###############################################################
#  Generated by:      Cadence Innovus 21.14-s109_1
#  OS:                Linux x86_64(Host ID miet-cad-edu)
#  Generated on:      Sat Nov 14 11:48:11 2026
#  Design:            statistics_unit
#  Command:           write_lef_abstract -stripe_pins -top_layer 5 -no_cut_obs ./out/statistics_unit.lef
###############################################################

VERSION 5.8 ;

BUSBITCHARS "[]" ;
DIVIDERCHAR "/" ;

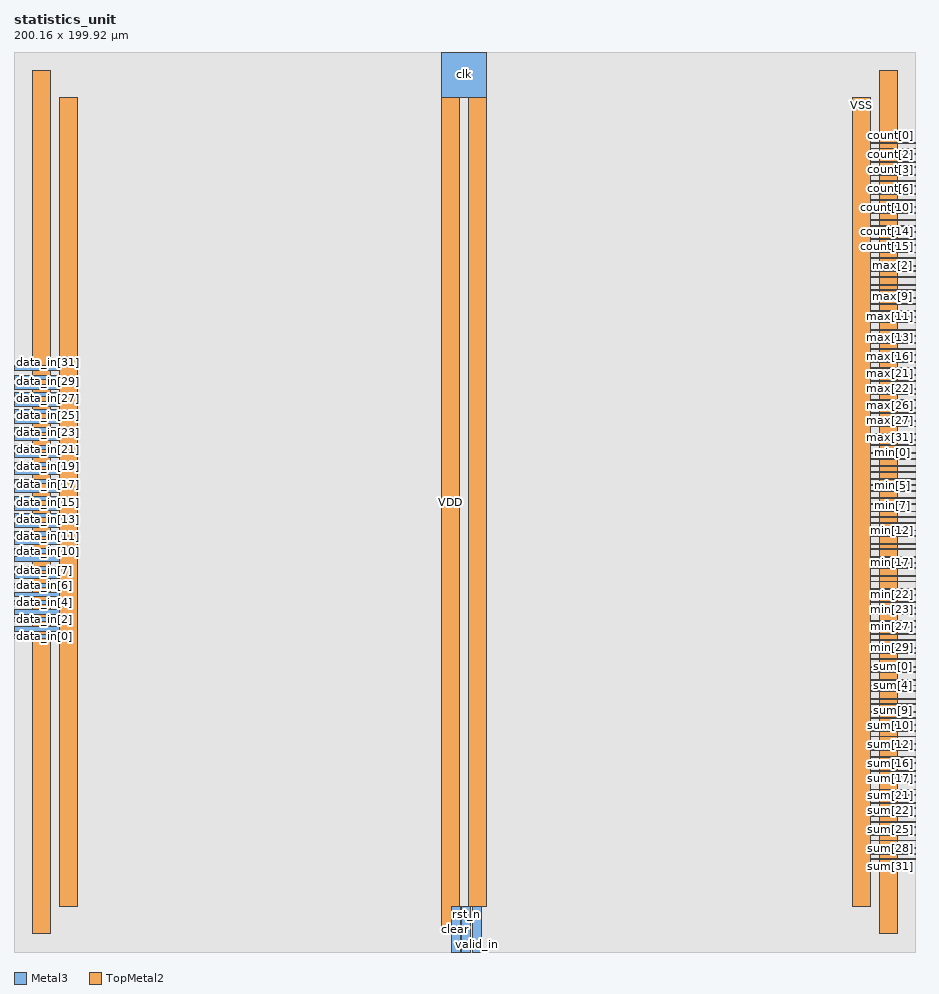
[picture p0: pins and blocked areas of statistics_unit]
MACRO statistics_unit
  CLASS BLOCK ;
  SIZE 200.160000 BY 199.920000 ;
  FOREIGN statistics_unit 0.000000 0.000000 ;
  ORIGIN 0 0 ;
  SYMMETRY X Y R90 ;
  PIN clk
    DIRECTION INPUT ;
    USE SIGNAL ;
    PORT
      LAYER Metal3 ;
        RECT 95.000000 189.920000 105.000000 199.920000 ;
    END
  END clk
  PIN rst_n
    DIRECTION INPUT ;
    USE SIGNAL ;
    PORT
      LAYER Metal3 ;
        RECT 99.480000 0.000000 101.480000 10.000000 ;
    END
  END rst_n
  PIN clear
    DIRECTION INPUT ;
    USE SIGNAL ;
    PORT
      LAYER Metal3 ;
        RECT 97.080000 0.000000 99.080000 10.000000 ;
    END
  END clear
  PIN valid_in
    DIRECTION INPUT ;
    USE SIGNAL ;
    PORT
      LAYER Metal3 ;
        RECT 101.880000 0.000000 103.880000 10.000000 ;
    END
  END valid_in
  PIN data_in[31]
    DIRECTION INPUT ;
    USE SIGNAL ;
    PORT
      LAYER Metal3 ;
        RECT 0.000000 129.260000 10.000000 130.260000 ;
    END
  END data_in[31]
  PIN data_in[30]
    DIRECTION INPUT ;
    USE SIGNAL ;
    PORT
      LAYER Metal3 ;
        RECT 0.000000 127.160000 10.000000 128.160000 ;
    END
  END data_in[30]
  PIN data_in[29]
    DIRECTION INPUT ;
    USE SIGNAL ;
    PORT
      LAYER Metal3 ;
        RECT 0.000000 125.060000 10.000000 126.060000 ;
    END
  END data_in[29]
  PIN data_in[28]
    DIRECTION INPUT ;
    USE SIGNAL ;
    PORT
      LAYER Metal3 ;
        RECT 0.000000 123.380000 10.000000 124.380000 ;
    END
  END data_in[28]
  PIN data_in[27]
    DIRECTION INPUT ;
    USE SIGNAL ;
    PORT
      LAYER Metal3 ;
        RECT 0.000000 121.280000 10.000000 122.280000 ;
    END
  END data_in[27]
  PIN data_in[26]
    DIRECTION INPUT ;
    USE SIGNAL ;
    PORT
      LAYER Metal3 ;
        RECT 0.000000 119.600000 10.000000 120.600000 ;
    END
  END data_in[26]
  PIN data_in[25]
    DIRECTION INPUT ;
    USE SIGNAL ;
    PORT
      LAYER Metal3 ;
        RECT 0.000000 117.500000 10.000000 118.500000 ;
    END
  END data_in[25]
  PIN data_in[24]
    DIRECTION INPUT ;
    USE SIGNAL ;
    PORT
      LAYER Metal3 ;
        RECT 0.000000 115.400000 10.000000 116.400000 ;
    END
  END data_in[24]
  PIN data_in[23]
    DIRECTION INPUT ;
    USE SIGNAL ;
    PORT
      LAYER Metal3 ;
        RECT 0.000000 113.720000 10.000000 114.720000 ;
    END
  END data_in[23]
  PIN data_in[22]
    DIRECTION INPUT ;
    USE SIGNAL ;
    PORT
      LAYER Metal3 ;
        RECT 0.000000 111.620000 10.000000 112.620000 ;
    END
  END data_in[22]
  PIN data_in[21]
    DIRECTION INPUT ;
    USE SIGNAL ;
    PORT
      LAYER Metal3 ;
        RECT 0.000000 109.940000 10.000000 110.940000 ;
    END
  END data_in[21]
  PIN data_in[20]
    DIRECTION INPUT ;
    USE SIGNAL ;
    PORT
      LAYER Metal3 ;
        RECT 0.000000 107.840000 10.000000 108.840000 ;
    END
  END data_in[20]
  PIN data_in[19]
    DIRECTION INPUT ;
    USE SIGNAL ;
    PORT
      LAYER Metal3 ;
        RECT 0.000000 106.160000 10.000000 107.160000 ;
    END
  END data_in[19]
  PIN data_in[18]
    DIRECTION INPUT ;
    USE SIGNAL ;
    PORT
      LAYER Metal3 ;
        RECT 0.000000 104.060000 10.000000 105.060000 ;
    END
  END data_in[18]
  PIN data_in[17]
    DIRECTION INPUT ;
    USE SIGNAL ;
    PORT
      LAYER Metal3 ;
        RECT 0.000000 101.960000 10.000000 102.960000 ;
    END
  END data_in[17]
  PIN data_in[16]
    DIRECTION INPUT ;
    USE SIGNAL ;
    PORT
      LAYER Metal3 ;
        RECT 0.000000 100.280000 10.000000 101.280000 ;
    END
  END data_in[16]
  PIN data_in[15]
    DIRECTION INPUT ;
    USE SIGNAL ;
    PORT
      LAYER Metal3 ;
        RECT 0.000000 98.180000 10.000000 99.180000 ;
    END
  END data_in[15]
  PIN data_in[14]
    DIRECTION INPUT ;
    USE SIGNAL ;
    PORT
      LAYER Metal3 ;
        RECT 0.000000 96.500000 10.000000 97.500000 ;
    END
  END data_in[14]
  PIN data_in[13]
    DIRECTION INPUT ;
    USE SIGNAL ;
    PORT
      LAYER Metal3 ;
        RECT 0.000000 94.400000 10.000000 95.400000 ;
    END
  END data_in[13]
  PIN data_in[12]
    DIRECTION INPUT ;
    USE SIGNAL ;
    PORT
      LAYER Metal3 ;
        RECT 0.000000 92.300000 10.000000 93.300000 ;
    END
  END data_in[12]
  PIN data_in[11]
    DIRECTION INPUT ;
    USE SIGNAL ;
    PORT
      LAYER Metal3 ;
        RECT 0.000000 90.620000 10.000000 91.620000 ;
    END
  END data_in[11]
  PIN data_in[10]
    DIRECTION INPUT ;
    USE SIGNAL ;
    PORT
      LAYER Metal3 ;
        RECT 0.000000 88.520000 10.000000 89.520000 ;
    END
  END data_in[10]
  PIN data_in[9]
    DIRECTION INPUT ;
    USE SIGNAL ;
    PORT
      LAYER Metal3 ;
        RECT 0.000000 86.840000 10.000000 87.840000 ;
    END
  END data_in[9]
  PIN data_in[8]
    DIRECTION INPUT ;
    USE SIGNAL ;
    PORT
      LAYER Metal3 ;
        RECT 0.000000 84.740000 10.000000 85.740000 ;
    END
  END data_in[8]
  PIN data_in[7]
    DIRECTION INPUT ;
    USE SIGNAL ;
    PORT
      LAYER Metal3 ;
        RECT 0.000000 83.060000 10.000000 84.060000 ;
    END
  END data_in[7]
  PIN data_in[6]
    DIRECTION INPUT ;
    USE SIGNAL ;
    PORT
      LAYER Metal3 ;
        RECT 0.000000 80.960000 10.000000 81.960000 ;
    END
  END data_in[6]
  PIN data_in[5]
    DIRECTION INPUT ;
    USE SIGNAL ;
    PORT
      LAYER Metal3 ;
        RECT 0.000000 78.860000 10.000000 79.860000 ;
    END
  END data_in[5]
  PIN data_in[4]
    DIRECTION INPUT ;
    USE SIGNAL ;
    PORT
      LAYER Metal3 ;
        RECT 0.000000 77.180000 10.000000 78.180000 ;
    END
  END data_in[4]
  PIN data_in[3]
    DIRECTION INPUT ;
    USE SIGNAL ;
    PORT
      LAYER Metal3 ;
        RECT 0.000000 75.080000 10.000000 76.080000 ;
    END
  END data_in[3]
  PIN data_in[2]
    DIRECTION INPUT ;
    USE SIGNAL ;
    PORT
      LAYER Metal3 ;
        RECT 0.000000 73.400000 10.000000 74.400000 ;
    END
  END data_in[2]
  PIN data_in[1]
    DIRECTION INPUT ;
    USE SIGNAL ;
    PORT
      LAYER Metal3 ;
        RECT 0.000000 71.300000 10.000000 72.300000 ;
    END
  END data_in[1]
  PIN data_in[0]
    DIRECTION INPUT ;
    USE SIGNAL ;
    PORT
      LAYER Metal3 ;
        RECT 0.000000 69.620000 10.000000 70.620000 ;
    END
  END data_in[0]
  PIN count[15]
    DIRECTION OUTPUT ;
    USE SIGNAL ;
    PORT
      LAYER Metal3 ;
        RECT 190.160000 158.220000 200.160000 158.420000 ;
    END
  END count[15]
  PIN count[14]
    DIRECTION OUTPUT ;
    USE SIGNAL ;
    PORT
      LAYER Metal3 ;
        RECT 190.160000 159.900000 200.160000 160.100000 ;
    END
  END count[14]
  PIN count[13]
    DIRECTION OUTPUT ;
    USE SIGNAL ;
    PORT
      LAYER Metal3 ;
        RECT 190.160000 161.160000 200.160000 161.360000 ;
    END
  END count[13]
  PIN count[12]
    DIRECTION OUTPUT ;
    USE SIGNAL ;
    PORT
      LAYER Metal3 ;
        RECT 190.160000 162.420000 200.160000 162.620000 ;
    END
  END count[12]
  PIN count[11]
    DIRECTION OUTPUT ;
    USE SIGNAL ;
    PORT
      LAYER Metal3 ;
        RECT 190.160000 164.100000 200.160000 164.300000 ;
    END
  END count[11]
  PIN count[10]
    DIRECTION OUTPUT ;
    USE SIGNAL ;
    PORT
      LAYER Metal3 ;
        RECT 190.160000 165.360000 200.160000 165.560000 ;
    END
  END count[10]
  PIN count[9]
    DIRECTION OUTPUT ;
    USE SIGNAL ;
    PORT
      LAYER Metal3 ;
        RECT 190.160000 167.040000 200.160000 167.240000 ;
    END
  END count[9]
  PIN count[8]
    DIRECTION OUTPUT ;
    USE SIGNAL ;
    PORT
      LAYER Metal3 ;
        RECT 190.160000 168.300000 200.160000 168.500000 ;
    END
  END count[8]
  PIN count[7]
    DIRECTION OUTPUT ;
    USE SIGNAL ;
    PORT
      LAYER Metal3 ;
        RECT 190.160000 169.980000 200.160000 170.180000 ;
    END
  END count[7]
  PIN count[6]
    DIRECTION OUTPUT ;
    USE SIGNAL ;
    PORT
      LAYER Metal3 ;
        RECT 190.160000 171.240000 200.160000 171.440000 ;
    END
  END count[6]
  PIN count[5]
    DIRECTION OUTPUT ;
    USE SIGNAL ;
    PORT
      LAYER Metal3 ;
        RECT 190.160000 172.500000 200.160000 172.700000 ;
    END
  END count[5]
  PIN count[4]
    DIRECTION OUTPUT ;
    USE SIGNAL ;
    PORT
      LAYER Metal3 ;
        RECT 190.160000 174.180000 200.160000 174.380000 ;
    END
  END count[4]
  PIN count[3]
    DIRECTION OUTPUT ;
    USE SIGNAL ;
    PORT
      LAYER Metal3 ;
        RECT 190.160000 175.440000 200.160000 175.640000 ;
    END
  END count[3]
  PIN count[2]
    DIRECTION OUTPUT ;
    USE SIGNAL ;
    PORT
      LAYER Metal3 ;
        RECT 190.160000 177.120000 200.160000 177.320000 ;
    END
  END count[2]
  PIN count[1]
    DIRECTION OUTPUT ;
    USE SIGNAL ;
    PORT
      LAYER Metal3 ;
        RECT 190.160000 178.380000 200.160000 178.580000 ;
    END
  END count[1]
  PIN count[0]
    DIRECTION OUTPUT ;
    USE SIGNAL ;
    PORT
      LAYER Metal3 ;
        RECT 190.160000 179.640000 200.160000 179.840000 ;
    END
  END count[0]
  PIN sum[31]
    DIRECTION OUTPUT ;
    USE SIGNAL ;
    PORT
      LAYER Metal3 ;
        RECT 190.160000 20.460000 200.160000 20.660000 ;
    END
  END sum[31]
  PIN sum[30]
    DIRECTION OUTPUT ;
    USE SIGNAL ;
    PORT
      LAYER Metal3 ;
        RECT 190.160000 21.720000 200.160000 21.920000 ;
    END
  END sum[30]
  PIN sum[29]
    DIRECTION OUTPUT ;
    USE SIGNAL ;
    PORT
      LAYER Metal3 ;
        RECT 190.160000 22.980000 200.160000 23.180000 ;
    END
  END sum[29]
  PIN sum[28]
    DIRECTION OUTPUT ;
    USE SIGNAL ;
    PORT
      LAYER Metal3 ;
        RECT 190.160000 24.660000 200.160000 24.860000 ;
    END
  END sum[28]
  PIN sum[27]
    DIRECTION OUTPUT ;
    USE SIGNAL ;
    PORT
      LAYER Metal3 ;
        RECT 190.160000 25.920000 200.160000 26.120000 ;
    END
  END sum[27]
  PIN sum[26]
    DIRECTION OUTPUT ;
    USE SIGNAL ;
    PORT
      LAYER Metal3 ;
        RECT 190.160000 27.600000 200.160000 27.800000 ;
    END
  END sum[26]
  PIN sum[25]
    DIRECTION OUTPUT ;
    USE SIGNAL ;
    PORT
      LAYER Metal3 ;
        RECT 190.160000 28.860000 200.160000 29.060000 ;
    END
  END sum[25]
  PIN sum[24]
    DIRECTION OUTPUT ;
    USE SIGNAL ;
    PORT
      LAYER Metal3 ;
        RECT 190.160000 30.120000 200.160000 30.320000 ;
    END
  END sum[24]
  PIN sum[23]
    DIRECTION OUTPUT ;
    USE SIGNAL ;
    PORT
      LAYER Metal3 ;
        RECT 190.160000 31.800000 200.160000 32.000000 ;
    END
  END sum[23]
  PIN sum[22]
    DIRECTION OUTPUT ;
    USE SIGNAL ;
    PORT
      LAYER Metal3 ;
        RECT 190.160000 33.060000 200.160000 33.260000 ;
    END
  END sum[22]
  PIN sum[21]
    DIRECTION OUTPUT ;
    USE SIGNAL ;
    PORT
      LAYER Metal3 ;
        RECT 190.160000 34.740000 200.160000 34.940000 ;
    END
  END sum[21]
  PIN sum[20]
    DIRECTION OUTPUT ;
    USE SIGNAL ;
    PORT
      LAYER Metal3 ;
        RECT 190.160000 36.000000 200.160000 36.200000 ;
    END
  END sum[20]
  PIN sum[19]
    DIRECTION OUTPUT ;
    USE SIGNAL ;
    PORT
      LAYER Metal3 ;
        RECT 190.160000 37.680000 200.160000 37.880000 ;
    END
  END sum[19]
  PIN sum[18]
    DIRECTION OUTPUT ;
    USE SIGNAL ;
    PORT
      LAYER Metal3 ;
        RECT 190.160000 38.940000 200.160000 39.140000 ;
    END
  END sum[18]
  PIN sum[17]
    DIRECTION OUTPUT ;
    USE SIGNAL ;
    PORT
      LAYER Metal3 ;
        RECT 190.160000 40.200000 200.160000 40.400000 ;
    END
  END sum[17]
  PIN sum[16]
    DIRECTION OUTPUT ;
    USE SIGNAL ;
    PORT
      LAYER Metal3 ;
        RECT 190.160000 41.880000 200.160000 42.080000 ;
    END
  END sum[16]
  PIN sum[15]
    DIRECTION OUTPUT ;
    USE SIGNAL ;
    PORT
      LAYER Metal3 ;
        RECT 190.160000 43.140000 200.160000 43.340000 ;
    END
  END sum[15]
  PIN sum[14]
    DIRECTION OUTPUT ;
    USE SIGNAL ;
    PORT
      LAYER Metal3 ;
        RECT 190.160000 44.820000 200.160000 45.020000 ;
    END
  END sum[14]
  PIN sum[13]
    DIRECTION OUTPUT ;
    USE SIGNAL ;
    PORT
      LAYER Metal3 ;
        RECT 190.160000 46.080000 200.160000 46.280000 ;
    END
  END sum[13]
  PIN sum[12]
    DIRECTION OUTPUT ;
    USE SIGNAL ;
    PORT
      LAYER Metal3 ;
        RECT 190.160000 47.760000 200.160000 47.960000 ;
    END
  END sum[12]
  PIN sum[11]
    DIRECTION OUTPUT ;
    USE SIGNAL ;
    PORT
      LAYER Metal3 ;
        RECT 190.160000 49.020000 200.160000 49.220000 ;
    END
  END sum[11]
  PIN sum[10]
    DIRECTION OUTPUT ;
    USE SIGNAL ;
    PORT
      LAYER Metal3 ;
        RECT 190.160000 50.280000 200.160000 50.480000 ;
    END
  END sum[10]
  PIN sum[9]
    DIRECTION OUTPUT ;
    USE SIGNAL ;
    PORT
      LAYER Metal3 ;
        RECT 190.160000 51.960000 200.160000 52.160000 ;
    END
  END sum[9]
  PIN sum[8]
    DIRECTION OUTPUT ;
    USE SIGNAL ;
    PORT
      LAYER Metal3 ;
        RECT 190.160000 53.220000 200.160000 53.420000 ;
    END
  END sum[8]
  PIN sum[7]
    DIRECTION OUTPUT ;
    USE SIGNAL ;
    PORT
      LAYER Metal3 ;
        RECT 190.160000 54.900000 200.160000 55.100000 ;
    END
  END sum[7]
  PIN sum[6]
    DIRECTION OUTPUT ;
    USE SIGNAL ;
    PORT
      LAYER Metal3 ;
        RECT 190.160000 56.160000 200.160000 56.360000 ;
    END
  END sum[6]
  PIN sum[5]
    DIRECTION OUTPUT ;
    USE SIGNAL ;
    PORT
      LAYER Metal3 ;
        RECT 190.160000 57.840000 200.160000 58.040000 ;
    END
  END sum[5]
  PIN sum[4]
    DIRECTION OUTPUT ;
    USE SIGNAL ;
    PORT
      LAYER Metal3 ;
        RECT 190.160000 59.100000 200.160000 59.300000 ;
    END
  END sum[4]
  PIN sum[3]
    DIRECTION OUTPUT ;
    USE SIGNAL ;
    PORT
      LAYER Metal3 ;
        RECT 190.160000 60.360000 200.160000 60.560000 ;
    END
  END sum[3]
  PIN sum[2]
    DIRECTION OUTPUT ;
    USE SIGNAL ;
    PORT
      LAYER Metal3 ;
        RECT 190.160000 62.040000 200.160000 62.240000 ;
    END
  END sum[2]
  PIN sum[1]
    DIRECTION OUTPUT ;
    USE SIGNAL ;
    PORT
      LAYER Metal3 ;
        RECT 190.160000 63.300000 200.160000 63.500000 ;
    END
  END sum[1]
  PIN sum[0]
    DIRECTION OUTPUT ;
    USE SIGNAL ;
    PORT
      LAYER Metal3 ;
        RECT 190.160000 64.980000 200.160000 65.180000 ;
    END
  END sum[0]
  PIN min[31]
    DIRECTION OUTPUT ;
    USE SIGNAL ;
    PORT
      LAYER Metal3 ;
        RECT 190.160000 66.240000 200.160000 66.440000 ;
    END
  END min[31]
  PIN min[30]
    DIRECTION OUTPUT ;
    USE SIGNAL ;
    PORT
      LAYER Metal3 ;
        RECT 190.160000 67.500000 200.160000 67.700000 ;
    END
  END min[30]
  PIN min[29]
    DIRECTION OUTPUT ;
    USE SIGNAL ;
    PORT
      LAYER Metal3 ;
        RECT 190.160000 69.180000 200.160000 69.380000 ;
    END
  END min[29]
  PIN min[28]
    DIRECTION OUTPUT ;
    USE SIGNAL ;
    PORT
      LAYER Metal3 ;
        RECT 190.160000 70.440000 200.160000 70.640000 ;
    END
  END min[28]
  PIN min[27]
    DIRECTION OUTPUT ;
    USE SIGNAL ;
    PORT
      LAYER Metal3 ;
        RECT 190.160000 72.120000 200.160000 72.320000 ;
    END
  END min[27]
  PIN min[26]
    DIRECTION OUTPUT ;
    USE SIGNAL ;
    PORT
      LAYER Metal3 ;
        RECT 190.160000 73.380000 200.160000 73.580000 ;
    END
  END min[26]
  PIN min[25]
    DIRECTION OUTPUT ;
    USE SIGNAL ;
    PORT
      LAYER Metal3 ;
        RECT 190.160000 75.060000 200.160000 75.260000 ;
    END
  END min[25]
  PIN min[24]
    DIRECTION OUTPUT ;
    USE SIGNAL ;
    PORT
      LAYER Metal3 ;
        RECT 190.160000 76.320000 200.160000 76.520000 ;
    END
  END min[24]
  PIN min[23]
    DIRECTION OUTPUT ;
    USE SIGNAL ;
    PORT
      LAYER Metal3 ;
        RECT 190.160000 77.580000 200.160000 77.780000 ;
    END
  END min[23]
  PIN min[22]
    DIRECTION OUTPUT ;
    USE SIGNAL ;
    PORT
      LAYER Metal3 ;
        RECT 190.160000 79.260000 200.160000 79.460000 ;
    END
  END min[22]
  PIN min[21]
    DIRECTION OUTPUT ;
    USE SIGNAL ;
    PORT
      LAYER Metal3 ;
        RECT 190.160000 80.520000 200.160000 80.720000 ;
    END
  END min[21]
  PIN min[20]
    DIRECTION OUTPUT ;
    USE SIGNAL ;
    PORT
      LAYER Metal3 ;
        RECT 190.160000 82.200000 200.160000 82.400000 ;
    END
  END min[20]
  PIN min[19]
    DIRECTION OUTPUT ;
    USE SIGNAL ;
    PORT
      LAYER Metal3 ;
        RECT 190.160000 83.460000 200.160000 83.660000 ;
    END
  END min[19]
  PIN min[18]
    DIRECTION OUTPUT ;
    USE SIGNAL ;
    PORT
      LAYER Metal3 ;
        RECT 190.160000 85.140000 200.160000 85.340000 ;
    END
  END min[18]
  PIN min[17]
    DIRECTION OUTPUT ;
    USE SIGNAL ;
    PORT
      LAYER Metal3 ;
        RECT 190.160000 86.400000 200.160000 86.600000 ;
    END
  END min[17]
  PIN min[16]
    DIRECTION OUTPUT ;
    USE SIGNAL ;
    PORT
      LAYER Metal3 ;
        RECT 190.160000 87.660000 200.160000 87.860000 ;
    END
  END min[16]
  PIN min[15]
    DIRECTION OUTPUT ;
    USE SIGNAL ;
    PORT
      LAYER Metal3 ;
        RECT 190.160000 89.340000 200.160000 89.540000 ;
    END
  END min[15]
  PIN min[14]
    DIRECTION OUTPUT ;
    USE SIGNAL ;
    PORT
      LAYER Metal3 ;
        RECT 190.160000 90.600000 200.160000 90.800000 ;
    END
  END min[14]
  PIN min[13]
    DIRECTION OUTPUT ;
    USE SIGNAL ;
    PORT
      LAYER Metal3 ;
        RECT 190.160000 92.280000 200.160000 92.480000 ;
    END
  END min[13]
  PIN min[12]
    DIRECTION OUTPUT ;
    USE SIGNAL ;
    PORT
      LAYER Metal3 ;
        RECT 190.160000 93.540000 200.160000 93.740000 ;
    END
  END min[12]
  PIN min[11]
    DIRECTION OUTPUT ;
    USE SIGNAL ;
    PORT
      LAYER Metal3 ;
        RECT 190.160000 95.220000 200.160000 95.420000 ;
    END
  END min[11]
  PIN min[10]
    DIRECTION OUTPUT ;
    USE SIGNAL ;
    PORT
      LAYER Metal3 ;
        RECT 190.160000 96.480000 200.160000 96.680000 ;
    END
  END min[10]
  PIN min[9]
    DIRECTION OUTPUT ;
    USE SIGNAL ;
    PORT
      LAYER Metal3 ;
        RECT 190.160000 97.740000 200.160000 97.940000 ;
    END
  END min[9]
  PIN min[8]
    DIRECTION OUTPUT ;
    USE SIGNAL ;
    PORT
      LAYER Metal3 ;
        RECT 190.160000 99.420000 200.160000 99.620000 ;
    END
  END min[8]
  PIN min[7]
    DIRECTION OUTPUT ;
    USE SIGNAL ;
    PORT
      LAYER Metal3 ;
        RECT 190.160000 100.680000 200.160000 100.880000 ;
    END
  END min[7]
  PIN min[6]
    DIRECTION OUTPUT ;
    USE SIGNAL ;
    PORT
      LAYER Metal3 ;
        RECT 190.160000 102.360000 200.160000 102.560000 ;
    END
  END min[6]
  PIN min[5]
    DIRECTION OUTPUT ;
    USE SIGNAL ;
    PORT
      LAYER Metal3 ;
        RECT 190.160000 103.620000 200.160000 103.820000 ;
    END
  END min[5]
  PIN min[4]
    DIRECTION OUTPUT ;
    USE SIGNAL ;
    PORT
      LAYER Metal3 ;
        RECT 190.160000 104.880000 200.160000 105.080000 ;
    END
  END min[4]
  PIN min[3]
    DIRECTION OUTPUT ;
    USE SIGNAL ;
    PORT
      LAYER Metal3 ;
        RECT 190.160000 106.560000 200.160000 106.760000 ;
    END
  END min[3]
  PIN min[2]
    DIRECTION OUTPUT ;
    USE SIGNAL ;
    PORT
      LAYER Metal3 ;
        RECT 190.160000 107.820000 200.160000 108.020000 ;
    END
  END min[2]
  PIN min[1]
    DIRECTION OUTPUT ;
    USE SIGNAL ;
    PORT
      LAYER Metal3 ;
        RECT 190.160000 109.500000 200.160000 109.700000 ;
    END
  END min[1]
  PIN min[0]
    DIRECTION OUTPUT ;
    USE SIGNAL ;
    PORT
      LAYER Metal3 ;
        RECT 190.160000 110.760000 200.160000 110.960000 ;
    END
  END min[0]
  PIN max[31]
    DIRECTION OUTPUT ;
    USE SIGNAL ;
    PORT
      LAYER Metal3 ;
        RECT 190.160000 112.440000 200.160000 112.640000 ;
    END
  END max[31]
  PIN max[30]
    DIRECTION OUTPUT ;
    USE SIGNAL ;
    PORT
      LAYER Metal3 ;
        RECT 190.160000 113.700000 200.160000 113.900000 ;
    END
  END max[30]
  PIN max[29]
    DIRECTION OUTPUT ;
    USE SIGNAL ;
    PORT
      LAYER Metal3 ;
        RECT 190.160000 114.960000 200.160000 115.160000 ;
    END
  END max[29]
  PIN max[28]
    DIRECTION OUTPUT ;
    USE SIGNAL ;
    PORT
      LAYER Metal3 ;
        RECT 190.160000 116.640000 200.160000 116.840000 ;
    END
  END max[28]
  PIN max[27]
    DIRECTION OUTPUT ;
    USE SIGNAL ;
    PORT
      LAYER Metal3 ;
        RECT 190.160000 117.900000 200.160000 118.100000 ;
    END
  END max[27]
  PIN max[26]
    DIRECTION OUTPUT ;
    USE SIGNAL ;
    PORT
      LAYER Metal3 ;
        RECT 190.160000 119.580000 200.160000 119.780000 ;
    END
  END max[26]
  PIN max[25]
    DIRECTION OUTPUT ;
    USE SIGNAL ;
    PORT
      LAYER Metal3 ;
        RECT 190.160000 120.840000 200.160000 121.040000 ;
    END
  END max[25]
  PIN max[24]
    DIRECTION OUTPUT ;
    USE SIGNAL ;
    PORT
      LAYER Metal3 ;
        RECT 190.160000 122.520000 200.160000 122.720000 ;
    END
  END max[24]
  PIN max[23]
    DIRECTION OUTPUT ;
    USE SIGNAL ;
    PORT
      LAYER Metal3 ;
        RECT 190.160000 123.780000 200.160000 123.980000 ;
    END
  END max[23]
  PIN max[22]
    DIRECTION OUTPUT ;
    USE SIGNAL ;
    PORT
      LAYER Metal3 ;
        RECT 190.160000 125.040000 200.160000 125.240000 ;
    END
  END max[22]
  PIN max[21]
    DIRECTION OUTPUT ;
    USE SIGNAL ;
    PORT
      LAYER Metal3 ;
        RECT 190.160000 126.720000 200.160000 126.920000 ;
    END
  END max[21]
  PIN max[20]
    DIRECTION OUTPUT ;
    USE SIGNAL ;
    PORT
      LAYER Metal3 ;
        RECT 190.160000 127.980000 200.160000 128.180000 ;
    END
  END max[20]
  PIN max[19]
    DIRECTION OUTPUT ;
    USE SIGNAL ;
    PORT
      LAYER Metal3 ;
        RECT 190.160000 129.660000 200.160000 129.860000 ;
    END
  END max[19]
  PIN max[18]
    DIRECTION OUTPUT ;
    USE SIGNAL ;
    PORT
      LAYER Metal3 ;
        RECT 190.160000 130.920000 200.160000 131.120000 ;
    END
  END max[18]
  PIN max[17]
    DIRECTION OUTPUT ;
    USE SIGNAL ;
    PORT
      LAYER Metal3 ;
        RECT 190.160000 132.600000 200.160000 132.800000 ;
    END
  END max[17]
  PIN max[16]
    DIRECTION OUTPUT ;
    USE SIGNAL ;
    PORT
      LAYER Metal3 ;
        RECT 190.160000 133.860000 200.160000 134.060000 ;
    END
  END max[16]
  PIN max[15]
    DIRECTION OUTPUT ;
    USE SIGNAL ;
    PORT
      LAYER Metal3 ;
        RECT 190.160000 135.120000 200.160000 135.320000 ;
    END
  END max[15]
  PIN max[14]
    DIRECTION OUTPUT ;
    USE SIGNAL ;
    PORT
      LAYER Metal3 ;
        RECT 190.160000 136.800000 200.160000 137.000000 ;
    END
  END max[14]
  PIN max[13]
    DIRECTION OUTPUT ;
    USE SIGNAL ;
    PORT
      LAYER Metal3 ;
        RECT 190.160000 138.060000 200.160000 138.260000 ;
    END
  END max[13]
  PIN max[12]
    DIRECTION OUTPUT ;
    USE SIGNAL ;
    PORT
      LAYER Metal3 ;
        RECT 190.160000 139.740000 200.160000 139.940000 ;
    END
  END max[12]
  PIN max[11]
    DIRECTION OUTPUT ;
    USE SIGNAL ;
    PORT
      LAYER Metal3 ;
        RECT 190.160000 141.000000 200.160000 141.200000 ;
    END
  END max[11]
  PIN max[10]
    DIRECTION OUTPUT ;
    USE SIGNAL ;
    PORT
      LAYER Metal3 ;
        RECT 190.160000 142.260000 200.160000 142.460000 ;
    END
  END max[10]
  PIN max[9]
    DIRECTION OUTPUT ;
    USE SIGNAL ;
    PORT
      LAYER Metal3 ;
        RECT 190.160000 143.940000 200.160000 144.140000 ;
    END
  END max[9]
  PIN max[8]
    DIRECTION OUTPUT ;
    USE SIGNAL ;
    PORT
      LAYER Metal3 ;
        RECT 190.160000 145.200000 200.160000 145.400000 ;
    END
  END max[8]
  PIN max[7]
    DIRECTION OUTPUT ;
    USE SIGNAL ;
    PORT
      LAYER Metal3 ;
        RECT 190.160000 146.880000 200.160000 147.080000 ;
    END
  END max[7]
  PIN max[6]
    DIRECTION OUTPUT ;
    USE SIGNAL ;
    PORT
      LAYER Metal3 ;
        RECT 190.160000 148.140000 200.160000 148.340000 ;
    END
  END max[6]
  PIN max[5]
    DIRECTION OUTPUT ;
    USE SIGNAL ;
    PORT
      LAYER Metal3 ;
        RECT 190.160000 149.820000 200.160000 150.020000 ;
    END
  END max[5]
  PIN max[4]
    DIRECTION OUTPUT ;
    USE SIGNAL ;
    PORT
      LAYER Metal3 ;
        RECT 190.160000 151.080000 200.160000 151.280000 ;
    END
  END max[4]
  PIN max[3]
    DIRECTION OUTPUT ;
    USE SIGNAL ;
    PORT
      LAYER Metal3 ;
        RECT 190.160000 152.340000 200.160000 152.540000 ;
    END
  END max[3]
  PIN max[2]
    DIRECTION OUTPUT ;
    USE SIGNAL ;
    PORT
      LAYER Metal3 ;
        RECT 190.160000 154.020000 200.160000 154.220000 ;
    END
  END max[2]
  PIN max[1]
    DIRECTION OUTPUT ;
    USE SIGNAL ;
    PORT
      LAYER Metal3 ;
        RECT 190.160000 155.280000 200.160000 155.480000 ;
    END
  END max[1]
  PIN max[0]
    DIRECTION OUTPUT ;
    USE SIGNAL ;
    PORT
      LAYER Metal3 ;
        RECT 190.160000 156.960000 200.160000 157.160000 ;
    END
  END max[0]
  PIN VSS
    DIRECTION INOUT ;
    USE GROUND ;

# P/G power stripe data as pin
    PORT
      LAYER TopMetal2 ;
        RECT 186.160000 10.000000 190.160000 189.920000 ;
        RECT 10.000000 10.000000 14.000000 189.920000 ;
        RECT 101.000000 10.000000 105.000000 189.920000 ;
    END
# end of P/G power stripe data as pin

  END VSS
  PIN VDD
    DIRECTION INOUT ;
    USE POWER ;

# P/G power stripe data as pin
    PORT
      LAYER TopMetal2 ;
        RECT 95.000000 4.000000 99.000000 195.920000 ;
        RECT 192.160000 4.000000 196.160000 195.920000 ;
        RECT 4.000000 4.000000 8.000000 195.920000 ;
    END
# end of P/G power stripe data as pin

  END VDD
  OBS
    LAYER Metal1 ;
      RECT 0.000000 0.000000 200.160000 199.920000 ;
    LAYER Metal2 ;
      RECT 0.000000 0.000000 200.160000 199.920000 ;
    LAYER Metal3 ;
      RECT 0.000000 0.000000 200.160000 199.920000 ;
    LAYER Metal4 ;
      RECT 0.000000 0.000000 200.160000 199.920000 ;
    LAYER Metal5 ;
      RECT 0.000000 0.000000 200.160000 199.920000 ;
  END
END statistics_unit

END LIBRARY
